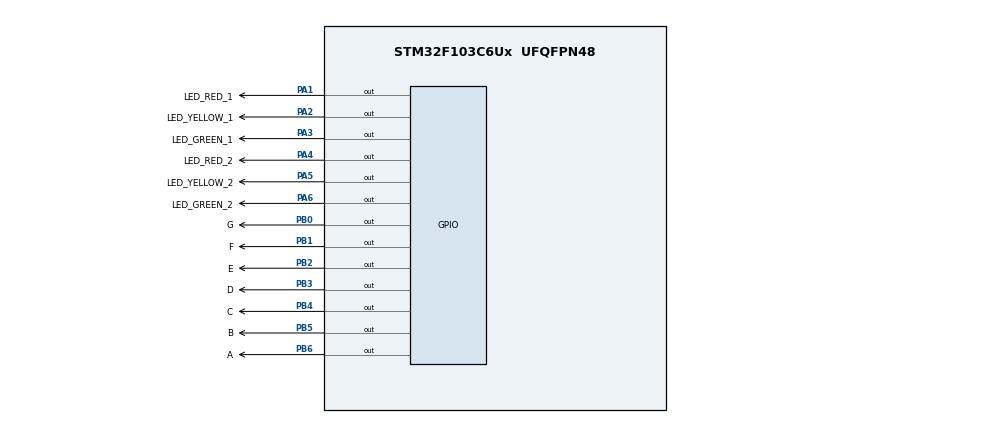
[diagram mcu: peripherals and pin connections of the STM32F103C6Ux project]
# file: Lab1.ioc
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Mcu.Family=STM32F1
Mcu.Name=STM32F103C6Ux
Mcu.Package=UFQFPN48
NVIC.PriorityGroup=NVIC_PRIORITYGROUP_4
PA1.GPIO_Label=LED_RED_1
PA1.Signal=GPIO_Output
PA2.GPIO_Label=LED_YELLOW_1
PA2.Signal=GPIO_Output
PA3.GPIO_Label=LED_GREEN_1
PA3.Signal=GPIO_Output
PA4.GPIO_Label=LED_RED_2
PA4.Signal=GPIO_Output
PA5.GPIO_Label=LED_YELLOW_2
PA5.Signal=GPIO_Output
PA6.GPIO_Label=LED_GREEN_2
PA6.Signal=GPIO_Output
PB0.GPIO_Label=G
PB0.Signal=GPIO_Output
PB1.GPIO_Label=F
PB1.Signal=GPIO_Output
PB2.GPIO_Label=E
PB2.Signal=GPIO_Output
PB3.GPIO_Label=D
PB3.Signal=GPIO_Output
PB4.GPIO_Label=C
PB4.Signal=GPIO_Output
PB5.GPIO_Label=B
PB5.Signal=GPIO_Output
PB6.GPIO_Label=A
PB6.Signal=GPIO_Output
ProjectManager.HeapSize=0x200
ProjectManager.StackSize=0x400
ProjectManager.TargetToolchain=STM32CubeIDE
RCC.APB1Freq_Value=8000000
RCC.APB2Freq_Value=8000000
VP_SYS_VS_ND.Mode=No_Debug
board=custom

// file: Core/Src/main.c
/* USER CODE BEGIN Header */
/**
  ******************************************************************************
  * @file           : main.c
  * @brief          : Main program body
  ******************************************************************************
  * @attention
  *
  * <h2><center>&copy; Copyright (c) 2023 STMicroelectronics.
  * All rights reserved.</center></h2>
  *
  * This software component is licensed by ST under BSD 3-Clause license,
  * the "License"; You may not use this file except in compliance with the
  * License. You may obtain a copy of the License at:
  *                        opensource.org/licenses/BSD-3-Clause
  *
  ******************************************************************************
  */
/* USER CODE END Header */
#include "main.h"

void SystemClock_Config(void);
static void MX_GPIO_Init(void);

void clearAllClock() {
	HAL_GPIO_WritePin(LED_12_GPIO_Port, LED_12_Pin, GPIO_PIN_SET);
	HAL_GPIO_WritePin(LED_11_GPIO_Port, LED_11_Pin, GPIO_PIN_SET);
	HAL_GPIO_WritePin(LED_10_GPIO_Port, LED_10_Pin, GPIO_PIN_SET);
	HAL_GPIO_WritePin(LED_9_GPIO_Port, LED_9_Pin, GPIO_PIN_SET);
	HAL_GPIO_WritePin(LED_8_GPIO_Port, LED_8_Pin, GPIO_PIN_SET);
	HAL_GPIO_WritePin(LED_7_GPIO_Port, LED_7_Pin, GPIO_PIN_SET);
	HAL_GPIO_WritePin(LED_6_GPIO_Port, LED_6_Pin, GPIO_PIN_SET);
	HAL_GPIO_WritePin(LED_5_GPIO_Port, LED_5_Pin, GPIO_PIN_SET);
	HAL_GPIO_WritePin(LED_4_GPIO_Port, LED_4_Pin, GPIO_PIN_SET);
	HAL_GPIO_WritePin(LED_3_GPIO_Port, LED_3_Pin, GPIO_PIN_SET);
	HAL_GPIO_WritePin(LED_2_GPIO_Port, LED_2_Pin, GPIO_PIN_SET);
	HAL_GPIO_WritePin(LED_1_GPIO_Port, LED_1_Pin, GPIO_PIN_SET);
}

void setNumberOnClock(int num) {
	switch(num) {
		case 11:
				HAL_GPIO_WritePin(LED_11_GPIO_Port, LED_11_Pin, GPIO_PIN_RESET);
				break;
		case 10:
				HAL_GPIO_WritePin(LED_10_GPIO_Port, LED_10_Pin, GPIO_PIN_RESET);
				break;
		case 9:
				HAL_GPIO_WritePin(LED_9_GPIO_Port, LED_9_Pin, GPIO_PIN_RESET);
				break;
		case 8:
				HAL_GPIO_WritePin(LED_8_GPIO_Port, LED_8_Pin, GPIO_PIN_RESET);
				break;
		case 7:
				HAL_GPIO_WritePin(LED_7_GPIO_Port, LED_7_Pin, GPIO_PIN_RESET);
				break;
		case 6:
				HAL_GPIO_WritePin(LED_6_GPIO_Port, LED_6_Pin, GPIO_PIN_RESET);
				break;
		case 5:
				HAL_GPIO_WritePin(LED_5_GPIO_Port, LED_5_Pin, GPIO_PIN_RESET);
				break;
		case 4:
				HAL_GPIO_WritePin(LED_4_GPIO_Port, LED_4_Pin, GPIO_PIN_RESET);
				break;
		case 3:
				HAL_GPIO_WritePin(LED_3_GPIO_Port, LED_3_Pin, GPIO_PIN_RESET);
				break;
		case 2:
				HAL_GPIO_WritePin(LED_2_GPIO_Port, LED_2_Pin, GPIO_PIN_RESET);
				break;
		case 1:
				HAL_GPIO_WritePin(LED_1_GPIO_Port, LED_1_Pin, GPIO_PIN_RESET);
				break;
		case 0:
				HAL_GPIO_WritePin(LED_12_GPIO_Port, LED_12_Pin, GPIO_PIN_RESET);
				break;
	}
}

void clearNumberOnClock(int num) {
	switch(num) {
		case 11:
				HAL_GPIO_WritePin(LED_11_GPIO_Port, LED_11_Pin, GPIO_PIN_SET);
				break;
		case 10:
				HAL_GPIO_WritePin(LED_10_GPIO_Port, LED_10_Pin, GPIO_PIN_SET);
				break;
		case 9:
				HAL_GPIO_WritePin(LED_9_GPIO_Port, LED_9_Pin, GPIO_PIN_SET);
				break;
		case 8:
				HAL_GPIO_WritePin(LED_8_GPIO_Port, LED_8_Pin, GPIO_PIN_SET);
				break;
		case 7:
				HAL_GPIO_WritePin(LED_7_GPIO_Port, LED_7_Pin, GPIO_PIN_SET);
				break;
		case 6:
				HAL_GPIO_WritePin(LED_6_GPIO_Port, LED_6_Pin, GPIO_PIN_SET);
				break;
		case 5:
				HAL_GPIO_WritePin(LED_5_GPIO_Port, LED_5_Pin, GPIO_PIN_SET);
				break;
		case 4:
				HAL_GPIO_WritePin(LED_4_GPIO_Port, LED_4_Pin, GPIO_PIN_SET);
				break;
		case 3:
				HAL_GPIO_WritePin(LED_3_GPIO_Port, LED_3_Pin, GPIO_PIN_SET);
				break;
		case 2:
				HAL_GPIO_WritePin(LED_2_GPIO_Port, LED_2_Pin, GPIO_PIN_SET);
				break;
		case 1:
				HAL_GPIO_WritePin(LED_1_GPIO_Port, LED_1_Pin, GPIO_PIN_SET);
				break;
		case 0:
				HAL_GPIO_WritePin(LED_12_GPIO_Port, LED_12_Pin, GPIO_PIN_SET);
				break;
	}
}

int main(void)
{

  /* MCU Configuration--------------------------------------------------------*/

  /* Reset of all peripherals, Initializes the Flash interface and the Systick. */
  HAL_Init();

  /* Configure the system clock */
  SystemClock_Config();

  /* Initialize all configured peripherals */
  MX_GPIO_Init();

  /* Infinite loop */
  /* USER CODE BEGIN WHILE */
  int check = 0;
  int prevSec = 0, prevMin = 0, prevHour = 0;
  int secCycle = 0, minCycle = 0;
  int curSec = 0, curMin = 0, curHour = 0;
  clearAllClock();
  setNumberOnClock(0);

  while (1)
  {
	  if(check == 5) {
		  check = 0;
		  prevSec = curSec;
		  curSec++;
	  }
	  if(curSec == 12) {
		  if(prevSec != curMin && prevSec != curHour) {
			  clearNumberOnClock(prevSec);
		  }
		  prevSec = 0;
		  curSec = 0;
		  secCycle++;
	  }
	  if(secCycle == 5) {
		  secCycle = 0;
		  prevMin = curMin;
		  curMin++;
	  }
	  if(curMin == 12) {
		  if(prevMin != curSec && prevMin != curHour) {
			  clearNumberOnClock(prevMin);
		  }
		  prevMin = 0;
		  curMin = 0;
		  minCycle++;
	  }
	  if(minCycle == 5) {
		  minCycle = 0;
		  prevHour = curHour;
		  curHour++;
	  }
	  if(curHour == 11) {
		  clearAllClock();
		  setNumberOnClock(0);
		  continue;
	  }

	  // Display second
	  if(prevSec != curMin && prevSec != curHour) {
		  clearNumberOnClock(prevSec);
	  }
	  setNumberOnClock(curSec);

	  // Display minute
	  if(prevMin != curSec && prevMin != curHour) {
		  clearNumberOnClock(prevMin);
	  }
	  setNumberOnClock(curMin);

	  // Display hour
	  if(prevHour != curMin && prevHour != curSec) {
		  clearNumberOnClock(prevHour);
	  }
	  setNumberOnClock(curHour);

	  check++;
	  HAL_Delay(10);
  }
  /* USER CODE END 3 */
}

void SystemClock_Config(void)
{
  RCC_OscInitTypeDef RCC_OscInitStruct = {0};
  RCC_ClkInitTypeDef RCC_ClkInitStruct = {0};

  /** Initializes the RCC Oscillators according to the specified parameters
  * in the RCC_OscInitTypeDef structure.
  */
  RCC_OscInitStruct.OscillatorType = RCC_OSCILLATORTYPE_HSI;
  RCC_OscInitStruct.HSIState = RCC_HSI_ON;
  RCC_OscInitStruct.HSICalibrationValue = RCC_HSICALIBRATION_DEFAULT;
  RCC_OscInitStruct.PLL.PLLState = RCC_PLL_NONE;
  if (HAL_RCC_OscConfig(&RCC_OscInitStruct) != HAL_OK)
  {
    Error_Handler();
  }
  /** Initializes the CPU, AHB and APB buses clocks
  */
  RCC_ClkInitStruct.ClockType = RCC_CLOCKTYPE_HCLK|RCC_CLOCKTYPE_SYSCLK
                              |RCC_CLOCKTYPE_PCLK1|RCC_CLOCKTYPE_PCLK2;
  RCC_ClkInitStruct.SYSCLKSource = RCC_SYSCLKSOURCE_HSI;
  RCC_ClkInitStruct.AHBCLKDivider = RCC_SYSCLK_DIV1;
  RCC_ClkInitStruct.APB1CLKDivider = RCC_HCLK_DIV1;
  RCC_ClkInitStruct.APB2CLKDivider = RCC_HCLK_DIV1;

  if (HAL_RCC_ClockConfig(&RCC_ClkInitStruct, FLASH_LATENCY_0) != HAL_OK)
  {
    Error_Handler();
  }
}

static void MX_GPIO_Init(void)
{
  GPIO_InitTypeDef GPIO_InitStruct = {0};

  /* GPIO Ports Clock Enable */
  __HAL_RCC_GPIOA_CLK_ENABLE();

  /*Configure GPIO pin Output Level */
  HAL_GPIO_WritePin(GPIOA, LED_1_Pin|LED_2_Pin|LED_3_Pin|LED_4_Pin
                          |LED_5_Pin|LED_6_Pin|LED_7_Pin|LED_8_Pin
                          |LED_9_Pin|LED_10_Pin|LED_11_Pin|LED_12_Pin, GPIO_PIN_RESET);

  /*Configure GPIO pins : LED_1_Pin LED_2_Pin LED_3_Pin LED_4_Pin
                           LED_5_Pin LED_6_Pin LED_7_Pin LED_8_Pin
                           LED_9_Pin LED_10_Pin LED_11_Pin LED_12_Pin */
  GPIO_InitStruct.Pin = LED_1_Pin|LED_2_Pin|LED_3_Pin|LED_4_Pin
                          |LED_5_Pin|LED_6_Pin|LED_7_Pin|LED_8_Pin
                          |LED_9_Pin|LED_10_Pin|LED_11_Pin|LED_12_Pin;
  GPIO_InitStruct.Mode = GPIO_MODE_OUTPUT_PP;
  GPIO_InitStruct.Pull = GPIO_NOPULL;
  GPIO_InitStruct.Speed = GPIO_SPEED_FREQ_LOW;
  HAL_GPIO_Init(GPIOA, &GPIO_InitStruct);

}

void Error_Handler(void)
{
    __disable_irq();
    while (1)
    {
    }
}

/************************ (C) COPYRIGHT STMicroelectronics *****END OF FILE****/
